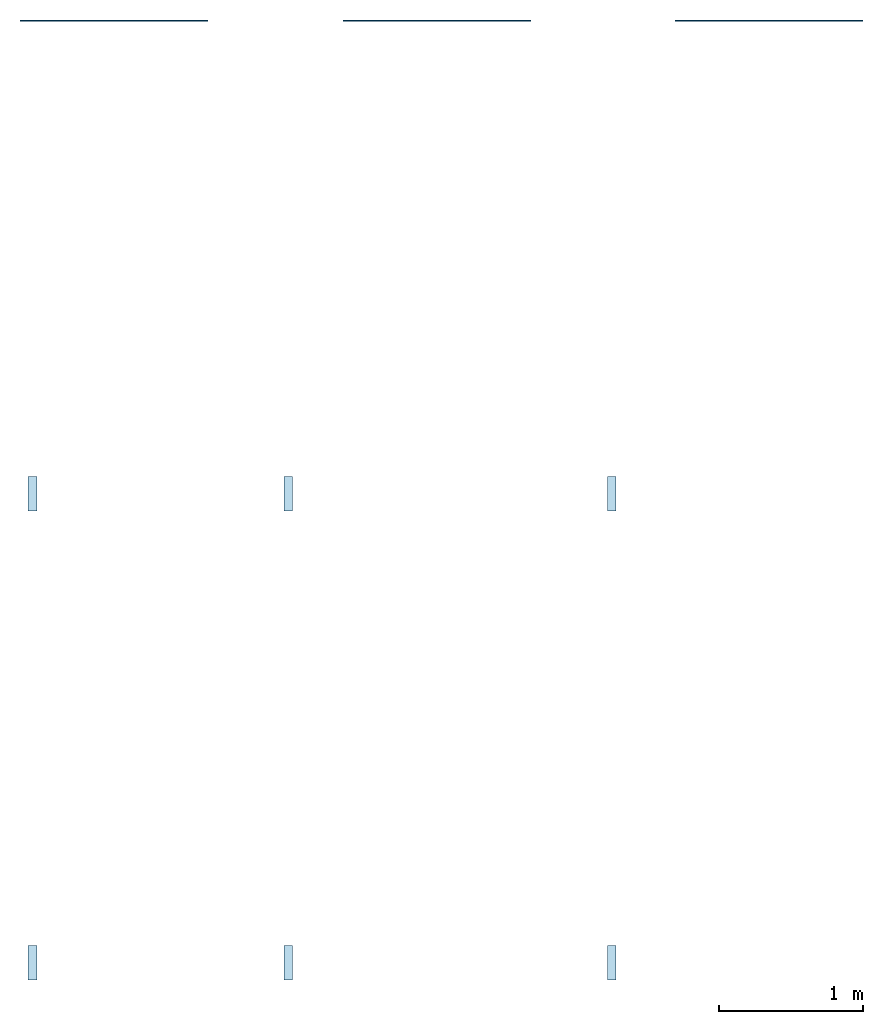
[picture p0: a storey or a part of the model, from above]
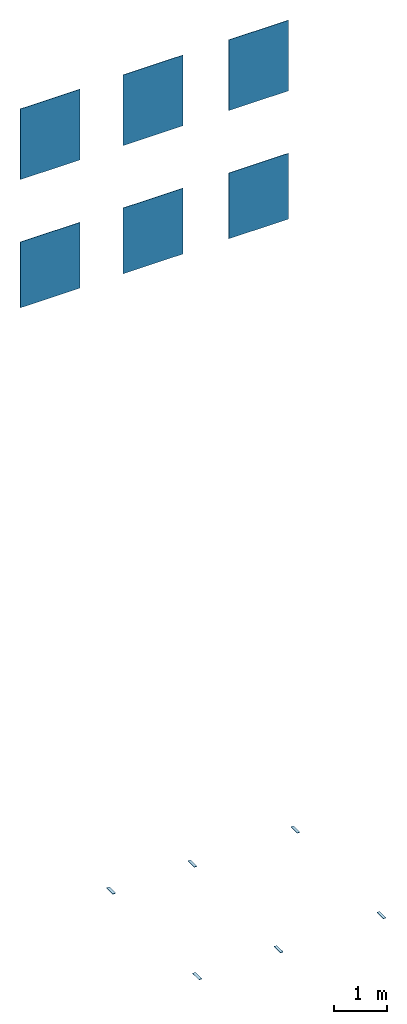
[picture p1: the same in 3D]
Properties of the parts of a building model (IFC2X3)

# File
Description: ViewDefinition [CoordinationView_V2.0], RevitIdentifiers [VersionGUID: c7997b9e-0f02-408a-b699-351949f842c8, NumberOfSaves: 537], CoordinateReference [CoordinateBase: Shared Coordinates, ProjectSite: Internal]
File name: Project Number
Time: 2023-12-12T10:03:28+01:00
Written by: ODA SDAI 24.3
Made in: Autodesk Revit 24.1.11.26 (ENU) - IFC 24.1.11.26

# IfcProject, Project Number
LongName: Refin-Blended; Phase: Project Status

# IfcSite, Default
RefLatitude: 51, 30, 0, 549316; RefLongitude: 0, -7, -34, -450321; RefElevation: 0 mm

# IfcBuilding
Pset_BuildingCommon - NumberOfStoreys: 1

# IfcBuildingStorey: Level:Circle Head - Project Datum (2)
Pset_AirSideSystemInformation - sets with these values: 2
Name | LongName = Name | Elevation (mm)
Level 0 | Level 0 | 0
Level 1 | Level 1 | 4000

# IfcSlab: Floor:Floor_Tiles_Refin-Halo-Basil-Lucido_6x24_OY76, Floor:Floor_Tiles_Refin-Halo-Basil-Lucido_6x24_OY76:364588
In: Level 0
Type - PredefinedType: FLOOR; Material: Halo-Basil-Lucido-6x24 OY76 8.5 mm, <Unnamed> 1 mm
Type - Pset_ConcreteElementGeneral - FireRating: INERT
Type - Pset_ElementShading - Color: GREEN
Type - Pset_FireRatingProperties - SurfaceSpreadOfFlame: INERT
Type - Pset_ManufacturerOccurrence - BarCode: N/A; SerialNumber: N/A
Type - Pset_ManufacturerTypeInformation - ArticleNumber: OY76; ModelReference: OY76; ModelLabel: BASIL LUCIDO 6X24; Manufacturer: info@refin.it; ProductionYear: N/A
Type - Pset_PrecastConcreteElementGeneral - SerialNumber: N/A
Type - Pset_ProductRequirements - Name: Halo_Basil_Lucido_6X24; Category: Pr_35_93_96_19:Ceramic tiles
Type - Pset_QuantityTakeOff - Reference: N/A
Type - Pset_ReinforcementBarPitchOfSlab - Description: PORCELAIN STONEWARE TILE; Reference: N/A
Type - Pset_SlabCommon - Reference: N/A; IsExternal: no; AcousticRating: N/A; FireRating: INERT; SurfaceSpreadOfFlame: INERT
Type - Pset_Warranty - WarrantyContent: N/A; Exclusions: N/A
Pset_QuantityTakeOff - sets with these values: 2
Pset_SlabCommon - LoadBearing: no; PitchAngle: 0 deg

# IfcSlab: Floor:Floor_Tiles_Refin-Halo-Cherry-Lucido_6x24_OY77, Floor:Floor_Tiles_Refin-Halo-Cherry-Lucido_6x24_OY77:367023
In: Level 0
Type - PredefinedType: FLOOR; Material: Halo-Cherry-Lucido-6x24 OY77 8.5 mm, <Unnamed> 1 mm
Type - Pset_ConcreteElementGeneral - FireRating: INERT
Type - Pset_ElementShading - Color: RED
Type - Pset_FireRatingProperties - SurfaceSpreadOfFlame: INERT
Type - Pset_ManufacturerOccurrence - BarCode: N/A; SerialNumber: N/A
Type - Pset_ManufacturerTypeInformation - ArticleNumber: OY77; ModelReference: OY77; ModelLabel: CHERRY LUCIDO 6X24; Manufacturer: info@refin.it; ProductionYear: N/A
Type - Pset_PrecastConcreteElementGeneral - SerialNumber: N/A
Type - Pset_ProductRequirements - Name: Halo_Cherry_Lucido_6X24; Category: Pr_35_93_96_19:Ceramic tiles
Type - Pset_QuantityTakeOff - Reference: N/A
Type - Pset_ReinforcementBarPitchOfSlab - Description: PORCELAIN STONEWARE TILE; Reference: N/A
Type - Pset_SlabCommon - Reference: N/A; IsExternal: no; AcousticRating: N/A; FireRating: INERT; SurfaceSpreadOfFlame: INERT
Type - Pset_Warranty - WarrantyContent: N/A; Exclusions: N/A
Pset_QuantityTakeOff - sets with these values: 2
Pset_SlabCommon - LoadBearing: no; PitchAngle: 0 deg

# IfcSlab: Floor:Floor_Tiles_Refin-Halo-Chrome-Lucido_6x24_OY79, Floor:Floor_Tiles_Refin-Halo-Chrome-Lucido_6x24_OY79:367149
In: Level 0
Type - PredefinedType: FLOOR; Material: Halo-Chrome-Lucido-6x24 OY79 8.5 mm, <Unnamed> 1 mm
Type - Pset_ConcreteElementGeneral - FireRating: INERT
Type - Pset_ElementShading - Color: GREY
Type - Pset_FireRatingProperties - SurfaceSpreadOfFlame: INERT
Type - Pset_ManufacturerOccurrence - BarCode: N/A; SerialNumber: N/A
Type - Pset_ManufacturerTypeInformation - ArticleNumber: OY79; ModelReference: OY79; ModelLabel: CHROME LUCIDO 6X24; Manufacturer: info@refin.it; ProductionYear: N/A
Type - Pset_PrecastConcreteElementGeneral - SerialNumber: N/A
Type - Pset_ProductRequirements - Name: Halo_Chrome_Lucido_6X24; Category: Pr_35_93_96_19:Ceramic tiles
Type - Pset_QuantityTakeOff - Reference: N/A
Type - Pset_ReinforcementBarPitchOfSlab - Description: PORCELAIN STONEWARE TILE; Reference: N/A
Type - Pset_SlabCommon - Reference: N/A; IsExternal: no; AcousticRating: N/A; FireRating: INERT; SurfaceSpreadOfFlame: INERT
Type - Pset_Warranty - WarrantyContent: N/A; Exclusions: N/A
Pset_QuantityTakeOff - sets with these values: 2
Pset_SlabCommon - LoadBearing: no; PitchAngle: 0 deg

# IfcSlab: Floor:Floor_Tiles_Refin-Halo-Cotton-Lucido_6x24_OY80, Floor:Floor_Tiles_Refin-Halo-Cotton-Lucido_6x24_OY80:367312
In: Level 0
Type - PredefinedType: FLOOR; Material: Halo-Cotton-Lucido-6x24 OY80 8.5 mm, <Unnamed> 1 mm
Type - Pset_ConcreteElementGeneral - FireRating: INERT
Type - Pset_ElementShading - Color: WHITE
Type - Pset_FireRatingProperties - SurfaceSpreadOfFlame: INERT
Type - Pset_ManufacturerOccurrence - BarCode: N/A; SerialNumber: N/A
Type - Pset_ManufacturerTypeInformation - ArticleNumber: OY80; ModelReference: OY80; ModelLabel: COTTON LUCIDO 6X24; Manufacturer: info@refin.it; ProductionYear: N/A
Type - Pset_PrecastConcreteElementGeneral - SerialNumber: N/A
Type - Pset_ProductRequirements - Name: Halo_Cotton_Lucido_6X24; Category: Pr_35_93_96_19:Ceramic tiles
Type - Pset_QuantityTakeOff - Reference: N/A
Type - Pset_ReinforcementBarPitchOfSlab - Description: PORCELAIN STONEWARE TILE; Reference: N/A
Type - Pset_SlabCommon - Reference: N/A; IsExternal: no; AcousticRating: N/A; FireRating: INERT; SurfaceSpreadOfFlame: INERT
Type - Pset_Warranty - WarrantyContent: N/A; Exclusions: N/A
Pset_QuantityTakeOff - sets with these values: 2
Pset_SlabCommon - LoadBearing: no; PitchAngle: 0 deg

# IfcSlab: Floor:Floor_Tiles_Refin-Halo-Ink-Lucido_6x24_OY81, Floor:Floor_Tiles_Refin-Halo-Ink-Lucido_6x24_OY81:367532
In: Level 0
Type - PredefinedType: FLOOR; Material: Halo-Ink-Lucido-6x24 OY81 8.5 mm, <Unnamed> 1 mm
Type - Pset_ConcreteElementGeneral - FireRating: INERT
Type - Pset_ElementShading - Color: BLACK
Type - Pset_FireRatingProperties - SurfaceSpreadOfFlame: INERT
Type - Pset_ManufacturerOccurrence - BarCode: N/A; SerialNumber: N/A
Type - Pset_ManufacturerTypeInformation - ArticleNumber: OY81; ModelReference: OY81; ModelLabel: INK LUCIDO 6X24; Manufacturer: info@refin.it; ProductionYear: N/A
Type - Pset_PrecastConcreteElementGeneral - SerialNumber: N/A
Type - Pset_ProductRequirements - Name: Halo_Ink_Lucido_6X24; Category: Pr_35_93_96_19:Ceramic tiles
Type - Pset_QuantityTakeOff - Reference: N/A
Type - Pset_ReinforcementBarPitchOfSlab - Description: PORCELAIN STONEWARE TILE; Reference: N/A
Type - Pset_SlabCommon - Reference: N/A; IsExternal: no; AcousticRating: N/A; FireRating: INERT; SurfaceSpreadOfFlame: INERT
Type - Pset_Warranty - WarrantyContent: N/A; Exclusions: N/A
Pset_QuantityTakeOff - sets with these values: 2
Pset_SlabCommon - LoadBearing: no; PitchAngle: 0 deg

# IfcSlab: Floor:Floor_Tiles_Refin-Halo-Ocean-Lucido_6x24_OY82, Floor:Floor_Tiles_Refin-Halo-Ocean-Lucido_6x24_OY82:367653
In: Level 0
Type - PredefinedType: FLOOR; Material: Halo-Ocean-Lucido-6x24 OY82 8.5 mm, <Unnamed> 1 mm
Type - Pset_ConcreteElementGeneral - FireRating: INERT
Type - Pset_ElementShading - Color: BLUE
Type - Pset_FireRatingProperties - SurfaceSpreadOfFlame: INERT
Type - Pset_ManufacturerOccurrence - BarCode: N/A; SerialNumber: N/A
Type - Pset_ManufacturerTypeInformation - ArticleNumber: OY82; ModelReference: OY82; ModelLabel: OCEAN LUCIDO 6X24; Manufacturer: info@refin.it; ProductionYear: N/A
Type - Pset_PrecastConcreteElementGeneral - SerialNumber: N/A
Type - Pset_ProductRequirements - Name: Halo_Ocean_Lucido_6X24; Category: Pr_35_93_96_19:Ceramic tiles
Type - Pset_QuantityTakeOff - Reference: N/A
Type - Pset_ReinforcementBarPitchOfSlab - Description: PORCELAIN STONEWARE TILE; Reference: N/A
Type - Pset_SlabCommon - Reference: N/A; IsExternal: no; AcousticRating: N/A; FireRating: INERT; SurfaceSpreadOfFlame: INERT
Type - Pset_Warranty - WarrantyContent: N/A; Exclusions: N/A
Pset_QuantityTakeOff - sets with these values: 2
Pset_SlabCommon - LoadBearing: no; PitchAngle: 0 deg

# IfcWallStandardCase: Basic Wall:Wall_Tiles_Refin-Halo-Basil-Lucido_6x24_OY76, Basic Wall:Wall_Tiles_Refin-Halo-Basil-Lucido_6x24_OY76:334895
In: Level 0
Type - PredefinedType: STANDARD; Material: <Unnamed> 1 mm, Halo-Basil-Lucido-6x24 OY76 8.5 mm
Type - Pset_ElementShading - Color: GREEN
Type - Pset_FireRatingProperties - SurfaceSpreadOfFlame: INERT
Type - Pset_ManufacturerOccurrence - BarCode: N/A; SerialNumber: N/A
Type - Pset_ManufacturerTypeInformation - ArticleNumber: OY76; ModelReference: OY76; ModelLabel: BASIL LUCIDO 6X24; Manufacturer: info@refin.it; ProductionYear: N/A
Type - Pset_PrecastConcreteElementGeneral - SerialNumber: N/A
Type - Pset_ProductRequirements - Name: Halo_Basil_Lucido_6X24; Category: Pr_35_93_96_19:Ceramic tiles
Type - Pset_QuantityTakeOff - Reference: N/A
Type - Pset_ReinforcementBarPitchOfWall - Description: PORCELAIN STONEWARE TILE; Reference: N/A
Type - Pset_WallCommon - Reference: N/A; IsExternal: no; AcousticRating: N/A; SurfaceSpreadOfFlame: INERT
Type - Pset_Warranty - WarrantyContent: N/A; Exclusions: N/A
Pset_QuantityTakeOff - sets with these values: 2
Pset_WallCommon - ExtendToStructure: no; LoadBearing: no

# IfcWallStandardCase: Basic Wall:Wall_Tiles_Refin-Halo-Cherry-Lucido_6x24_OY77, Basic Wall:Wall_Tiles_Refin-Halo-Cherry-Lucido_6x24_OY77:363313
In: Level 0
Type - PredefinedType: STANDARD; Material: <Unnamed> 1 mm, Halo-Cherry-Lucido-6x24 OY77 8.5 mm
Type - Pset_ElementShading - Color: RED
Type - Pset_FireRatingProperties - SurfaceSpreadOfFlame: INERT
Type - Pset_ManufacturerOccurrence - BarCode: N/A; SerialNumber: N/A
Type - Pset_ManufacturerTypeInformation - ArticleNumber: OY77; ModelReference: OY77; ModelLabel: CHERRY LUCIDO 6X24; Manufacturer: info@refin.it; ProductionYear: N/A
Type - Pset_PrecastConcreteElementGeneral - SerialNumber: N/A
Type - Pset_ProductRequirements - Name: Halo_Cherry_Lucido_6X24; Category: Pr_35_93_96_19:Ceramic tiles
Type - Pset_QuantityTakeOff - Reference: N/A
Type - Pset_ReinforcementBarPitchOfWall - Description: PORCELAIN STONEWARE TILE; Reference: N/A
Type - Pset_WallCommon - Reference: N/A; IsExternal: no; AcousticRating: N/A; SurfaceSpreadOfFlame: INERT
Type - Pset_Warranty - WarrantyContent: N/A; Exclusions: N/A
Pset_QuantityTakeOff - sets with these values: 2
Pset_WallCommon - ExtendToStructure: no; LoadBearing: no

# IfcWallStandardCase: Basic Wall:Wall_Tiles_Refin-Halo-Chrome-Lucido_6x24_OY79, Basic Wall:Wall_Tiles_Refin-Halo-Chrome-Lucido_6x24_OY79:363798
In: Level 0
Type - PredefinedType: STANDARD; Material: <Unnamed> 1 mm, Halo-Chrome-Lucido-6x24 OY79 8.5 mm
Type - Pset_ElementShading - Color: GREY
Type - Pset_FireRatingProperties - SurfaceSpreadOfFlame: INERT
Type - Pset_ManufacturerOccurrence - BarCode: N/A; SerialNumber: N/A
Type - Pset_ManufacturerTypeInformation - ArticleNumber: OY79; ModelReference: OY79; ModelLabel: CHROME LUCIDO 6X24; Manufacturer: info@refin.it; ProductionYear: N/A
Type - Pset_PrecastConcreteElementGeneral - SerialNumber: N/A
Type - Pset_ProductRequirements - Name: Halo_Chrome_Lucido_6X24; Category: Pr_35_93_96_19:Ceramic tiles
Type - Pset_QuantityTakeOff - Reference: N/A
Type - Pset_ReinforcementBarPitchOfWall - Description: PORCELAIN STONEWARE TILE; Reference: N/A
Type - Pset_WallCommon - Reference: N/A; IsExternal: no; AcousticRating: N/A; SurfaceSpreadOfFlame: INERT
Type - Pset_Warranty - WarrantyContent: N/A; Exclusions: N/A
Pset_QuantityTakeOff - sets with these values: 2
Pset_WallCommon - ExtendToStructure: no; LoadBearing: no

# IfcWallStandardCase: Basic Wall:Wall_Tiles_Refin-Halo-Cotton-Lucido_6x24_OY80, Basic Wall:Wall_Tiles_Refin-Halo-Cotton-Lucido_6x24_OY80:364401
In: Level 0
Type - PredefinedType: STANDARD; Material: <Unnamed> 1 mm, Halo-Cotton-Lucido-6x24 OY80 8.5 mm
Type - Pset_ElementShading - Color: WHITE
Type - Pset_FireRatingProperties - SurfaceSpreadOfFlame: INERT
Type - Pset_ManufacturerOccurrence - BarCode: N/A; SerialNumber: N/A
Type - Pset_ManufacturerTypeInformation - ArticleNumber: OY80; ModelReference: OY80; ModelLabel: COTTON LUCIDO 6X24; Manufacturer: info@refin.it; ProductionYear: N/A
Type - Pset_PrecastConcreteElementGeneral - SerialNumber: N/A
Type - Pset_ProductRequirements - Name: Halo_Cotton_Lucido_6X24; Category: Pr_35_93_96_19:Ceramic tiles
Type - Pset_QuantityTakeOff - Reference: N/A
Type - Pset_ReinforcementBarPitchOfWall - Description: PORCELAIN STONEWARE TILE; Reference: N/A
Type - Pset_WallCommon - Reference: N/A; IsExternal: no; AcousticRating: N/A; SurfaceSpreadOfFlame: INERT
Type - Pset_Warranty - WarrantyContent: N/A; Exclusions: N/A
Pset_QuantityTakeOff - sets with these values: 2
Pset_WallCommon - ExtendToStructure: no; LoadBearing: no

# IfcWallStandardCase: Basic Wall:Wall_Tiles_Refin-Halo-Ink-Lucido_6x24_OY81, Basic Wall:Wall_Tiles_Refin-Halo-Ink-Lucido_6x24_OY81:365073
In: Level 0
Type - PredefinedType: STANDARD; Material: <Unnamed> 1 mm, Halo-Ink-Lucido-6x24 OY81 8.5 mm
Type - Pset_ElementShading - Color: BLACK
Type - Pset_FireRatingProperties - SurfaceSpreadOfFlame: INERT
Type - Pset_ManufacturerOccurrence - BarCode: N/A; SerialNumber: N/A
Type - Pset_ManufacturerTypeInformation - ArticleNumber: OY81; ModelReference: OY81; ModelLabel: INK LUCIDO 6X24; Manufacturer: info@refin.it; ProductionYear: N/A
Type - Pset_PrecastConcreteElementGeneral - SerialNumber: N/A
Type - Pset_ProductRequirements - Name: Halo_Ink_Lucido_6X24; Category: Pr_35_93_96_19:Ceramic tiles
Type - Pset_QuantityTakeOff - Reference: N/A
Type - Pset_ReinforcementBarPitchOfWall - Description: PORCELAIN STONEWARE TILE; Reference: N/A
Type - Pset_WallCommon - Reference: N/A; IsExternal: no; AcousticRating: N/A; SurfaceSpreadOfFlame: INERT
Type - Pset_Warranty - WarrantyContent: N/A; Exclusions: N/A
Pset_QuantityTakeOff - sets with these values: 2
Pset_WallCommon - ExtendToStructure: no; LoadBearing: no

# IfcWallStandardCase: Basic Wall:Wall_Tiles_Refin-Halo-Ocean-Lucido_6x24_OY82, Basic Wall:Wall_Tiles_Refin-Halo-Ocean-Lucido_6x24_OY82:367672
In: Level 0
Type - PredefinedType: STANDARD; Material: <Unnamed> 1 mm, Halo-Ocean-Lucido-6x24 OY82 8.5 mm
Type - Pset_ElementShading - Color: BLUE
Type - Pset_FireRatingProperties - SurfaceSpreadOfFlame: INERT
Type - Pset_ManufacturerOccurrence - BarCode: N/A; SerialNumber: N/A
Type - Pset_ManufacturerTypeInformation - ArticleNumber: OY82; ModelReference: OY82; ModelLabel: OCEAN LUCIDO 6X24; Manufacturer: info@refin.it; ProductionYear: N/A
Type - Pset_PrecastConcreteElementGeneral - SerialNumber: N/A
Type - Pset_ProductRequirements - Name: Halo_Ocean_Lucido_6X24; Category: Pr_35_93_96_19:Ceramic tiles
Type - Pset_QuantityTakeOff - Reference: N/A
Type - Pset_ReinforcementBarPitchOfWall - Description: PORCELAIN STONEWARE TILE; Reference: N/A
Type - Pset_WallCommon - Reference: N/A; IsExternal: no; AcousticRating: N/A; SurfaceSpreadOfFlame: INERT
Type - Pset_Warranty - WarrantyContent: N/A; Exclusions: N/A
Pset_QuantityTakeOff - sets with these values: 2
Pset_WallCommon - ExtendToStructure: no; LoadBearing: no
